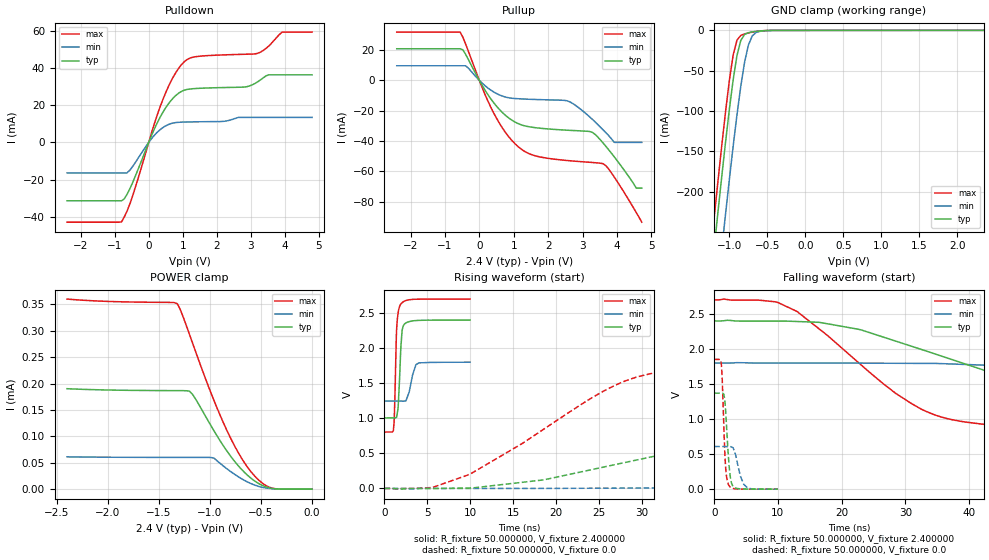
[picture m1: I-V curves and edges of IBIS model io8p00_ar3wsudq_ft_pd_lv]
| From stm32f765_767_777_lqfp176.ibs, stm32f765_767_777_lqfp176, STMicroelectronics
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|   Model io8p00_ar3wsudq_ft_pd_lv
[Model]  io8p00_ar3wsudq_ft_pd_lv
Model_type I/O
Polarity   Non-Inverting
Enable   Active-Low
Vinl =   0.720000V
Vinh =   1.680000V
Vmeas =  1.200000V
Cref =   50.000000pF
Rref =   100.000000M
Vref =   0.0V
C_comp   3.740200pF   3.683500pF   3.822900pF
[Temperature Range]   25.000000   0.125000k   -40.000000
[Pullup Reference]   2.400000V   1.800000V   2.700000V
[Pulldown Reference]   0.0V   0.0V   0.0V
[POWER Clamp Reference]   2.400000V   1.800000V   2.700000V
[GND Clamp Reference]   0.0V   0.0V   0.0V
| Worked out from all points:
|   slope of the pulldown table from 0 to 0.36 V, typ, clamps not added: 25 ohm
|   slope of the pullup table from 0 to 0.36 V, typ, clamps not added: 27.7 ohm
|   GND clamp passes 1 mA (typ) near -0.62 V on its own axis
|   rising waveform, R_fixture 50.000000, V_fixture 2.400000: 20-80 % time 329ps typ, 642ps min, 255ps max; typ from 1 V to 2.4 V
|   rising waveform, R_fixture 50.000000, V_fixture 0.0: 20-80 % time 32.3ns typ, 81.1ns min, 14.8ns max; typ from 0 V to 1.37 V
|   falling waveform, R_fixture 50.000000, V_fixture 2.400000: 20-80 % time 29.1ns typ, 72.6ns min, 15.7ns max; typ from 2.4 V to 1 V
|   falling waveform, R_fixture 50.000000, V_fixture 0.0: 20-80 % time 592ps typ, 1.02ns min, 461ps max; typ from 1.37 V to 0 V
[Pulldown]
|Voltage   I(typ)   I(min)   I(max)
-2.4V     -31.47mA   -16.45mA   -43.01mA
-800mV    -31.47mA   -16.45mA   -42.85mA
-480mV    -21.98mA   -13.17mA   -29.2mA
80mV      3.63mA     1.966mA    5.014mA
480mV     18.15mA    8.738mA    26.02mA
800mV     25.38mA    10.72mA    37.77mA
1.12V     28.53mA    11.02mA    44.6mA
2.8V      29.84mA    13.51mA    47.53mA
3.2V      32.66mA    13.51mA    48.04mA
3.52V     36.44mA    13.51mA    51.84mA
3.92V     36.44mA    13.51mA    59.49mA
4.8V      36.44mA    13.51mA    59.49mA
[Pullup]
|Voltage   I(typ)   I(min)   I(max)
-2.4V     20.89mA    9.66mA     31.89mA
-560mV    20.89mA    9.66mA     31.89mA
-400mV    17.28mA    9.66mA     24.06mA
320mV     -11.75mA   -6.207mA   -17.08mA
960mV     -26.47mA   -11.82mA   -40.02mA
1.52V     -30.88mA   -12.51mA   -49.05mA
2.56V     -32.88mA   -13.52mA   -52.9mA
3.28V     -34.25mA   -25.64mA   -54.18mA
3.6V      -41.44mA   -32.74mA   -55.03mA
3.92V     -50.46mA   -40.9mA    -63.79mA
4.56V     -71.1mA    -40.9mA    -87.26mA
4.72V     -71.1mA    -40.9mA    -93.6mA
[GND_clamp]
|Voltage   I(typ)   I(min)   I(max)
-2.4V     -1.43A     -1.515A    -1.399A
-1.25V    -315.9mA   -407.2mA   -278.2mA
-1.2V     -270.1mA   -361.3mA   -232.1mA
-1.15V    -225mA     -316mA     -186.8mA
-1.1V     -180.9mA   -271.3mA   -142.7mA
-1.05V    -138.2mA   -227.5mA   -100.5mA
-950mV    -61.14mA   -143.6mA   -30.44mA
-900mV    -31.24mA   -104.7mA   -12.15mA
-850mV    -12.5mA    -69.41mA   -6.236mA
-750mV    -2.91mA    -18.35mA   -3.195mA
-600mV    -761.5uA   -1.227mA   -751.9uA
2.35V     58.09uA    37.93uA    67.25uA
[POWER_clamp]
|Voltage   I(typ)   I(min)   I(max)
-2.4V     190.2uA    61.19uA    359.9uA
-1.32V    186.6uA    60.14uA    351.2uA
-1.29V    186.5uA    60.13uA    339.6uA
-1.2V     185.4uA    60.11uA    292.6uA
-1.17V    179.2uA    60.11uA    276.3uA
-960mV    110.2uA    58.62uA    167.5uA
-870mV    82.44uA    43.99uA    126.3uA
-750mV    50.58uA    26.92uA    78.64uA
-630mV    25.94uA    13.41uA    41.02uA
-510mV    9.22uA     4.527uA    14.97uA
-420mV    2.425uA    1.38uA     3.75uA
0V        0A         0A         0A
[Ramp]
| variable   typ   min   max
dV/dt_r  0.82230/32.32787n   0.36218/83.54610n   1.11060/14.76107n
dV/dt_f  0.83814/29.18374n   0.32664/73.67429n   1.13737/15.68093n
R_load = 50.000000
[Rising Waveform]
R_fixture= 50.000000
V_fixture= 2.400000
V_fixture_min= 1.800000
V_fixture_max= 2.700000
|time   V(typ)   V(min)   V(max)
0s        1.005V     1.245V     804.1mV
1.041ns   1.005V     1.245V     830.5mV
1.141ns   1.005V     1.245V     1.003V
1.421ns   1.018V     1.246V     2.284V
1.602ns   1.184V     1.246V     2.511V
1.882ns   1.947V     1.245V     2.624V
2.042ns   2.24V      1.245V     2.647V
2.262ns   2.332V     1.245V     2.666V
4.024ns   2.396V     1.789V     2.697V
9.97ns    2.399V     1.799V     2.699V
[Rising Waveform]
R_fixture= 50.000000
V_fixture= 0.0
V_fixture_min= 0.0
V_fixture_max= 0.0
|time   V(typ)   V(min)   V(max)
0s        6.354nV    356.5nV    2.716nV
5.506ns   -209.1uV   -118.7uV   13.13mV
9.51ns    5.648mV    -61.67uV   182.7mV
26.53ns   331.2mV    4.598mV    1.45V
31.53ns   462.1mV    7.176mV    1.651V
36.54ns   611.9mV    21.79mV    1.738V
55.56ns   1.077V     80.48mV    1.825V
77.08ns   1.305V     178.8mV    1.846V
148.1ns   1.368V     492.4mV    1.851V
249.2ns   1.369V     608.5mV    1.851V
[Falling Waveform]
R_fixture= 50.000000
V_fixture= 2.400000
V_fixture_min= 1.800000
V_fixture_max= 2.700000
|time   V(typ)   V(min)   V(max)
0s        2.399V     1.799V     2.699V
10.01ns   2.397V     1.798V     2.662V
13.01ns   2.391V     1.798V     2.533V
22.52ns   2.282V     1.798V     1.813V
31.03ns   2.036V     1.794V     1.216V
42.54ns   1.69V      1.768V     923.1mV
58.56ns   1.263V     1.716V     848.5mV
83.58ns   1.083V     1.578V     815.9mV
176.2ns   1.01V      1.275V     804.4mV
249.2ns   1.005V     1.245V     804.1mV
[Falling Waveform]
R_fixture= 50.000000
V_fixture= 0.0
V_fixture_min= 0.0
V_fixture_max= 0.0
|time   V(typ)   V(min)   V(max)
0s        1.369V     608.5mV    1.851V
1.141ns   1.369V     608.4mV    1.76V
1.722ns   1.206V     608.1mV    415.6mV
1.902ns   954.7mV    607.9mV    204.3mV
2.282ns   402.7mV    608.8mV    57.89mV
2.543ns   164mV      608.6mV    28.42mV
2.923ns   46.31mV    592.1mV    12.32mV
4.104ns   4.358mV    186.2mV    1.428mV
5.285ns   1.125mV    13.85mV    534.5uV
9.97ns    6.354nV    356.5nV    2.716nV
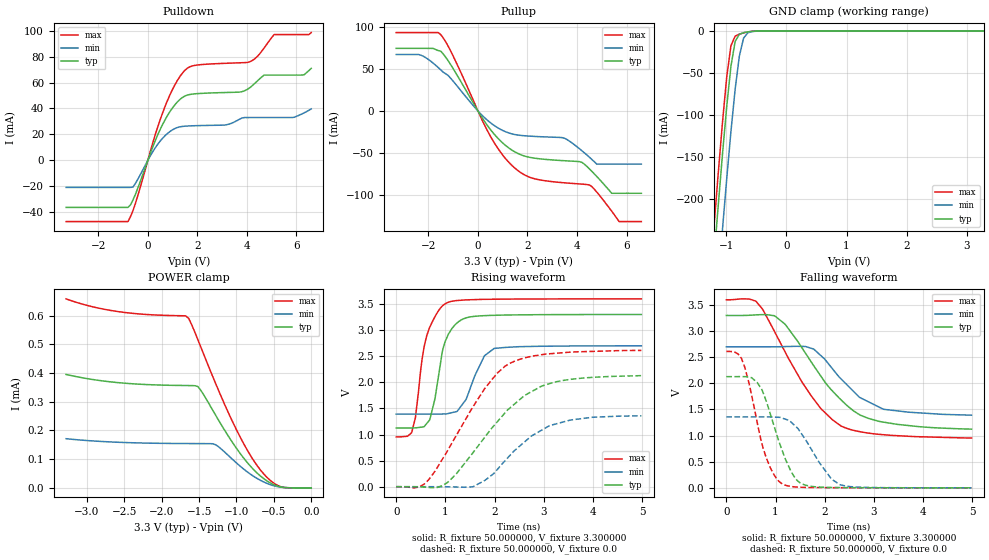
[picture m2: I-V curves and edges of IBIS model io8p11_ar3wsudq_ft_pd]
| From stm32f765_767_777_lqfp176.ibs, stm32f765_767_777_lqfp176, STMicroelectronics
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|   Model io8p11_ar3wsudq_ft_pd
[Model]  io8p11_ar3wsudq_ft_pd
Model_type I/O
Polarity   Non-Inverting
Enable   Active-Low
Vinl =   0.990000V
Vinh =   2.310000V
Vmeas =  1.650000V
Cref =   30.000000pF
Rref =   100.000000M
Vref =   0.0V
C_comp   3.843200pF   3.761700pF   3.937000pF
[Temperature Range]   25.000000   0.125000k   -40.000000
[Pullup Reference]   3.300000V   2.700000V   3.600000V
[Pulldown Reference]   0.0V   0.0V   0.0V
[POWER Clamp Reference]   3.300000V   2.700000V   3.600000V
[GND Clamp Reference]   0.0V   0.0V   0.0V
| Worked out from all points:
|   slope of the pulldown table from 0 to 0.495 V, typ, clamps not added: 20.9 ohm
|   slope of the pullup table from 0 to 0.495 V, typ, clamps not added: 22.6 ohm
|   GND clamp passes 1 mA (typ) near -0.62 V on its own axis
|   rising waveform, R_fixture 50.000000, V_fixture 3.300000: 20-80 % time 279ps typ, 352ps min, 279ps max; typ from 1.12 V to 3.3 V
|   rising waveform, R_fixture 50.000000, V_fixture 0.0: 20-80 % time 1.18ns typ, 960ps min, 1.04ns max; typ from 0 V to 2.13 V
|   falling waveform, R_fixture 50.000000, V_fixture 3.300000: 20-80 % time 1.07ns typ, 856ps min, 1.02ns max; typ from 3.3 V to 1.12 V
|   falling waveform, R_fixture 50.000000, V_fixture 0.0: 20-80 % time 466ps typ, 565ps min, 397ps max; typ from 2.13 V to 0 V
[Pulldown]
|Voltage   I(typ)   I(min)   I(max)
-3.3V     -36.18mA   -20.77mA   -47.07mA
-800mV    -36.18mA   -20.77mA   -47.07mA
-600mV    -30.5mA    -20.52mA   -38.69mA
700mV     31.4mA     19.11mA    41.71mA
1.2V      45.15mA    25.37mA    61.75mA
1.6V      50.35mA    26.5mA     71.06mA
3.1V      52.27mA    27.26mA    74.75mA
4.1V      55.7mA     33.01mA    75.8mA
4.7V      65.73mA    33.01mA    86.69mA
5.1V      65.73mA    33.01mA    96.89mA
6.3V      65.85mA    36.49mA    96.89mA
6.6V      70.9mA     39.7mA     98.44mA
[Pullup]
|Voltage   I(typ)   I(min)   I(max)
-3.3V     74.74mA    67.41mA    93.6mA
-2.3V     74.74mA    66.57mA    93.6mA
-1.5V     71.36mA    49.01mA    91.03mA
500mV     -22.07mA   -14mA      -30.03mA
1.6V      -50.64mA   -28.81mA   -70.96mA
3.5V      -59.53mA   -32.72mA   -85.92mA
4.2V      -61.52mA   -47.62mA   -87.46mA
4.5V      -69.21mA   -55.27mA   -88.44mA
4.8V      -78.37mA   -63.6mA    -97.02mA
5.4V      -98.4mA    -63.6mA    -119.7mA
5.7V      -98.4mA    -63.6mA    -132.2mA
6.6V      -98.4mA    -63.6mA    -132.2mA
[GND_clamp]
|Voltage   I(typ)   I(min)   I(max)
-3.3V     -2.324A    -2.403A    -2.297A
-1.2V     -270.2mA   -361.4mA   -232.1mA
-1.13V    -207.3mA   -298.1mA   -169mA
-1.06V    -146.7mA   -236.2mA   -108.8mA
-990mV    -90.18mA   -176.4mA   -54.97mA
-920mV    -42.21mA   -120mA     -17.69mA
-850mV    -12.58mA   -69.47mA   -6.279mA
-780mV    -3.983mA   -30.01mA   -3.9mA
-710mV    -2.112mA   -8.623mA   -2.396mA
-640mV    -1.159mA   -2.292mA   -1.234mA
-570mV    -535.1uA   -830.5uA   -490.2uA
3.28V     81.28uA    57.87uA    93.98uA
[POWER_clamp]
|Voltage   I(typ)   I(min)   I(max)
-3.28V    395.3uA    171.3uA    658.7uA
-2.6V     367.1uA    159uA      614.9uA
-1.68V    356.7uA    154.4uA    599.4uA
-1.64V    356.5uA    154.4uA    590.8uA
-1.52V    353.6uA    154.3uA    518.3uA
-1.48V    341.1uA    154.2uA    492.3uA
-1.28V    253.6uA    150.4uA    364.2uA
-960mV    123.1uA    77.56uA    181.6uA
-720mV    50.52uA    32.03uA    76.18uA
-560mV    18.94uA    12.27uA    28.65uA
-440mV    5.104uA    3.69uA     7.327uA
0V        0A         0A         0A
[Ramp]
| variable   typ   min   max
dV/dt_r  1.25826/1.16576n   0.79980/0.94582n   1.55946/1.04010n
dV/dt_f  1.27470/1.04927n   0.76302/0.82395n   1.56887/1.01446n
R_load = 50.000000
[Rising Waveform]
R_fixture= 50.000000
V_fixture= 3.300000
V_fixture_min= 2.700000
V_fixture_max= 3.600000
|time   V(typ)   V(min)   V(max)
0s        1.123V     1.391V     953.9mV
320.3ps   1.125V     1.391V     1.055V
390.4ps   1.127V     1.391V     1.324V
560.6ps   1.147V     1.391V     2.642V
680.7ps   1.281V     1.39V      3.05V
1.011ns   2.815V     1.394V     3.513V
1.421ns   3.234V     1.672V     3.578V
1.792ns   3.276V     2.504V     3.589V
1.992ns   3.283V     2.649V     3.591V
4.985ns   3.299V     2.699V     3.598V
[Rising Waveform]
R_fixture= 50.000000
V_fixture= 0.0
V_fixture_min= 0.0
V_fixture_max= 0.0
|time   V(typ)   V(min)   V(max)
0s        345.3uV    196.3uV    650.7uV
570.6ps   -7.29mV    186.7uV    49.82mV
1.061ns   94.14mV    -2.414mV   718.3mV
1.562ns   652.1mV    -573.3uV   1.531V
2.042ns   1.229V     314.7mV    2.162V
2.282ns   1.485V     568.6mV    2.348V
2.613ns   1.749V     860.6mV    2.468V
3.123ns   1.976V     1.171V     2.547V
3.994ns   2.095V     1.331V     2.592V
4.985ns   2.127V     1.357V     2.611V
[Falling Waveform]
R_fixture= 50.000000
V_fixture= 3.300000
V_fixture_min= 2.700000
V_fixture_max= 3.600000
|time   V(typ)   V(min)   V(max)
0s        3.299V     2.699V     3.598V
600.6ps   3.31V      2.699V     3.571V
740.7ps   3.314V     2.699V     3.413V
981ps     3.293V     2.7V       2.989V
1.201ns   3.124V     2.703V     2.59V
1.772ns   2.344V     2.657V     1.704V
2.342ns   1.675V     2.076V     1.178V
2.713ns   1.398V     1.73V      1.075V
3.193ns   1.258V     1.504V     1.017V
4.985ns   1.123V     1.391V     953.9mV
[Falling Waveform]
R_fixture= 50.000000
V_fixture= 0.0
V_fixture_min= 0.0
V_fixture_max= 0.0
|time   V(typ)   V(min)   V(max)
0s        2.127V     1.357V     2.611V
310.3ps   2.128V     1.357V     2.471V
470.5ps   2.115V     1.357V     1.964V
630.6ps   2.014V     1.357V     1.239V
880.9ps   1.455V     1.358V     413mV
1.131ns   727.2mV    1.337V     80.89mV
1.502ns   95.33mV    1.073V     12.51mV
2.132ns   7.615mV    175.2mV    3.177mV
2.312ns   5.456mV    59.47mV    2.808mV
4.985ns   345.3uV    196.3uV    650.7uV
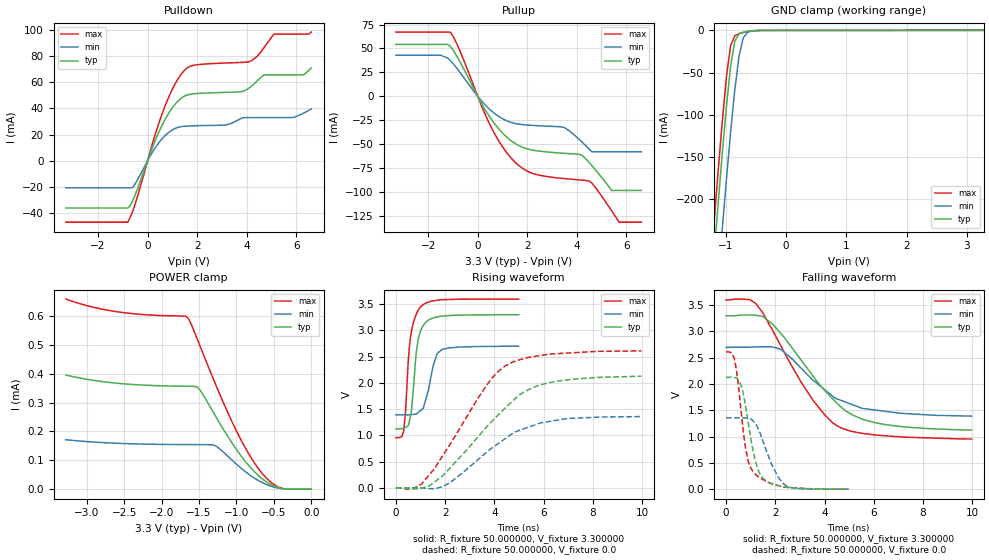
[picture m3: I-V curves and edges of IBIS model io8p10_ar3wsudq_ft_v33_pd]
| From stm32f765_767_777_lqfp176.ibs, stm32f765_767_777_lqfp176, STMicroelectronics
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|   Model io8p10_ar3wsudq_ft_v33_pd
[Model]  io8p10_ar3wsudq_ft_v33_pd
Model_type I/O
Polarity   Non-Inverting
Enable   Active-Low
Vinl =   0.990000V
Vinh =   2.310000V
Vmeas =  1.650000V
Cref =   40.000000pF
Rref =   100.000000M
Vref =   0.0V
C_comp   3.857500pF   3.760500pF   3.941700pF
[Temperature Range]   25.000000   0.125000k   -40.000000
[Pullup Reference]   3.300000V   2.700000V   3.600000V
[Pulldown Reference]   0.0V   0.0V   0.0V
[POWER Clamp Reference]   3.300000V   2.700000V   3.600000V
[GND Clamp Reference]   0.0V   0.0V   0.0V
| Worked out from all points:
|   slope of the pulldown table from 0 to 0.495 V, typ, clamps not added: 20.9 ohm
|   slope of the pullup table from 0 to 0.495 V, typ, clamps not added: 22.6 ohm
|   GND clamp passes 1 mA (typ) near -0.62 V on its own axis
|   rising waveform, R_fixture 50.000000, V_fixture 3.300000: 20-80 % time 278ps typ, 400ps min, 275ps max; typ from 1.12 V to 3.3 V
|   rising waveform, R_fixture 50.000000, V_fixture 0.0: 20-80 % time 2.56ns typ, 2.3ns min, 2.13ns max; typ from 0 V to 2.13 V
|   falling waveform, R_fixture 50.000000, V_fixture 3.300000: 20-80 % time 2.28ns typ, 2.11ns min, 2.06ns max; typ from 3.3 V to 1.12 V
|   falling waveform, R_fixture 50.000000, V_fixture 0.0: 20-80 % time 515ps typ, 708ps min, 441ps max; typ from 2.13 V to 0 V
[Pulldown]
|Voltage   I(typ)   I(min)   I(max)
-3.3V     -36.18mA   -20.77mA   -47.07mA
-800mV    -36.18mA   -20.77mA   -47.07mA
-600mV    -30.5mA    -20.52mA   -38.69mA
700mV     31.4mA     19.11mA    41.71mA
1.2V      45.15mA    25.37mA    61.75mA
1.6V      50.35mA    26.5mA     71.06mA
3.1V      52.27mA    27.26mA    74.75mA
4.1V      55.7mA     32.99mA    75.8mA
4.7V      65.71mA    32.99mA    86.63mA
5.1V      65.71mA    32.99mA    96.88mA
6.3V      65.85mA    36.49mA    96.88mA
6.6V      70.9mA     39.7mA     98.44mA
[Pullup]
|Voltage   I(typ)   I(min)   I(max)
-3.3V     54.18mA    42.91mA    67.09mA
-1.5V     54.18mA    42.91mA    67.09mA
-1.1V     51.95mA    37.28mA    66.83mA
500mV     -22.07mA   -14mA      -30.03mA
1.5V      -49.1mA    -28.3mA    -68.56mA
2.2V      -56.04mA   -30.32mA   -80.35mA
3.5V      -59.53mA   -32.72mA   -85.92mA
4.2V      -61.52mA   -47.6mA    -87.46mA
4.5V      -69.21mA   -55.15mA   -88.44mA
5.4V      -98.3mA    -57.9mA    -119.4mA
5.7V      -98.3mA    -57.9mA    -131.4mA
6.6V      -98.3mA    -57.9mA    -131.4mA
[GND_clamp]
|Voltage   I(typ)   I(min)   I(max)
-3.3V     -2.332A    -2.407A    -2.312A
-1.2V     -270.2mA   -361.4mA   -232.1mA
-1.13V    -207.3mA   -298.1mA   -169mA
-1.06V    -146.7mA   -236.2mA   -108.8mA
-990mV    -90.18mA   -176.4mA   -54.97mA
-920mV    -42.21mA   -120mA     -17.69mA
-850mV    -12.58mA   -69.47mA   -6.279mA
-780mV    -3.983mA   -30.01mA   -3.9mA
-710mV    -2.112mA   -8.623mA   -2.396mA
-640mV    -1.159mA   -2.292mA   -1.234mA
-570mV    -535.1uA   -830.5uA   -490.2uA
3.28V     81.28uA    57.87uA    93.98uA
[POWER_clamp]
|Voltage   I(typ)   I(min)   I(max)
-3.28V    395.3uA    171.3uA    658.7uA
-2.6V     367.1uA    159uA      614.9uA
-1.68V    356.7uA    154.4uA    599.4uA
-1.64V    356.5uA    154.4uA    590.8uA
-1.52V    353.6uA    154.3uA    518.3uA
-1.48V    341.1uA    154.2uA    492.3uA
-1.28V    253.6uA    150.4uA    364.2uA
-960mV    123.1uA    77.55uA    181.6uA
-720mV    50.52uA    32.03uA    76.18uA
-560mV    18.94uA    12.27uA    28.65uA
-440mV    5.104uA    3.69uA     7.327uA
0V        0A         0A         0A
[Ramp]
| variable   typ   min   max
dV/dt_r  1.26810/2.56020n   0.81246/2.31714n   1.56504/2.13233n
dV/dt_f  1.28472/2.27343n   0.77808/2.11211n   1.57535/2.06094n
R_load = 50.000000
[Rising Waveform]
R_fixture= 50.000000
V_fixture= 3.300000
V_fixture_min= 2.700000
V_fixture_max= 3.600000
|time   V(typ)   V(min)   V(max)
0s        1.123V     1.391V     953.8mV
320.3ps   1.131V     1.39V      1.098V
390.4ps   1.15V      1.39V      1.454V
510.5ps   1.199V     1.391V     2.476V
690.7ps   1.782V     1.398V     3.113V
840.8ps   2.632V     1.412V     3.325V
991ps     2.977V     1.47V      3.446V
1.682ns   3.258V     2.565V     3.576V
1.882ns   3.273V     2.639V     3.586V
4.985ns   3.299V     2.699V     3.598V
[Rising Waveform]
R_fixture= 50.000000
V_fixture= 0.0
V_fixture_min= 0.0
V_fixture_max= 0.0
|time   V(typ)   V(min)   V(max)
0s        196.3uV    83.65uV    714.9uV
560.6ps   -9.814mV   -61.21uV   -21.7mV
1.041ns   -6.992mV   -4.667mV   73.37mV
1.361ns   40.28mV    -15.48mV   251.5mV
2.182ns   370.6mV    92.42mV    818.3mV
3.804ns   1.221V     725.5mV    2.029V
4.505ns   1.555V     958.8mV    2.34V
5.165ns   1.816V     1.12V      2.46V
6.226ns   2.004V     1.263V     2.547V
9.97ns    2.127V     1.358V     2.611V
[Falling Waveform]
R_fixture= 50.000000
V_fixture= 3.300000
V_fixture_min= 2.700000
V_fixture_max= 3.600000
|time   V(typ)   V(min)   V(max)
0s        3.299V     2.699V     3.598V
961ps     3.313V     2.701V     3.604V
1.201ns   3.309V     2.706V     3.534V
1.502ns   3.282V     2.709V     3.345V
2.222ns   2.962V     2.662V     2.729V
3.524ns   2.157V     2.077V     1.697V
4.525ns   1.627V     1.715V     1.202V
5.185ns   1.4V       1.599V     1.091V
6.386ns   1.234V     1.486V     1.019V
9.97ns    1.123V     1.391V     953.8mV
[Falling Waveform]
R_fixture= 50.000000
V_fixture= 0.0
V_fixture_min= 0.0
V_fixture_max= 0.0
|time   V(typ)   V(min)   V(max)
0s        2.127V     1.358V     2.611V
340.3ps   2.124V     1.357V     2.473V
500.5ps   2.08V      1.357V     1.97V
650.7ps   1.925V     1.357V     1.314V
890.9ps   1.292V     1.346V     549.8mV
1.171ns   575.4mV    1.261V     293.2mV
1.542ns   192.7mV    852mV      171.1mV
2.132ns   64.87mV    216.9mV    66.89mV
2.422ns   39.32mV    72.24mV    35.98mV
4.985ns   196.3uV    83.65uV    714.9uV
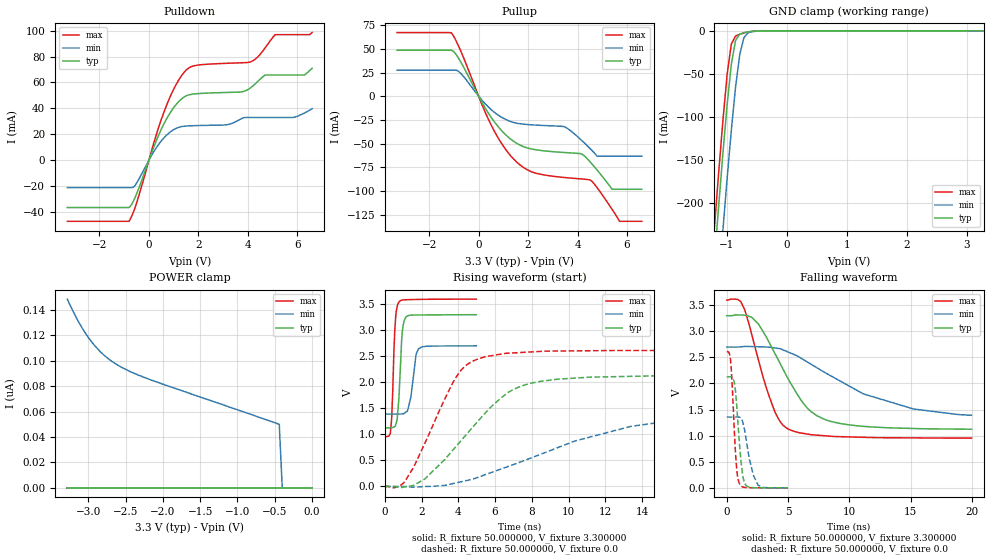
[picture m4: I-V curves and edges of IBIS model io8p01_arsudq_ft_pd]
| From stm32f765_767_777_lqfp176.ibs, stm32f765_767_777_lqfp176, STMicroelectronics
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|   Model io8p01_arsudq_ft_pd
[Model]  io8p01_arsudq_ft_pd
Model_type I/O
Polarity   Non-Inverting
Enable   Active-Low
Vinl =   0.990000V
Vinh =   2.310000V
Vmeas =  1.650000V
Cref =   50.000000pF
Rref =   100.000000M
Vref =   0.0V
C_comp   2.292100pF   2.228000pF   2.366600pF
[Temperature Range]   25.000000   0.125000k   -40.000000
[Pullup Reference]   3.300000V   2.700000V   3.600000V
[Pulldown Reference]   0.0V   0.0V   0.0V
[POWER Clamp Reference]   3.300000V   2.700000V   3.600000V
[GND Clamp Reference]   0.0V   0.0V   0.0V
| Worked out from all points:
|   slope of the pulldown table from 0 to 0.495 V, typ, clamps not added: 20.9 ohm
|   slope of the pullup table from 0 to 0.495 V, typ, clamps not added: 22.6 ohm
|   GND clamp passes 1 mA (typ) near -0.62 V on its own axis
|   rising waveform, R_fixture 50.000000, V_fixture 3.300000: 20-80 % time 192ps typ, 292ps min, 165ps max; typ from 1.12 V to 3.3 V
|   rising waveform, R_fixture 50.000000, V_fixture 0.0: 20-80 % time 3.34ns typ, 6.83ns min, 2.09ns max; typ from 0 V to 2.13 V
|   falling waveform, R_fixture 50.000000, V_fixture 3.300000: 20-80 % time 3.17ns typ, 6.84ns min, 1.99ns max; typ from 3.3 V to 1.12 V
|   falling waveform, R_fixture 50.000000, V_fixture 0.0: 20-80 % time 433ps typ, 669ps min, 341ps max; typ from 2.13 V to 0 V
[Pulldown]
|Voltage   I(typ)   I(min)   I(max)
-3.3V     -36.46mA   -21.1mA    -47.09mA
-800mV    -36.46mA   -21.1mA    -47.09mA
-600mV    -30.5mA    -20.54mA   -38.69mA
700mV     31.4mA     19.11mA    41.71mA
1.2V      45.15mA    25.37mA    61.75mA
1.6V      50.35mA    26.5mA     71.06mA
3.1V      52.27mA    27.26mA    74.75mA
4.1V      55.7mA     32.99mA    75.8mA
4.7V      65.72mA    32.99mA    86.69mA
5.1V      65.72mA    32.99mA    96.9mA
6.3V      65.87mA    36.5mA     96.9mA
6.6V      70.93mA    39.71mA    98.5mA
[Pullup]
|Voltage   I(typ)   I(min)   I(max)
-3.3V     48.54mA    27.43mA    67.18mA
-1.1V     48.54mA    27.43mA    66.9mA
-700mV    35.13mA    23.47mA    46.35mA
500mV     -22.07mA   -14mA      -30.03mA
1.5V      -49.1mA    -28.3mA    -68.56mA
2.2V      -56.04mA   -30.32mA   -80.35mA
3.5V      -59.53mA   -32.65mA   -85.92mA
4.5V      -69.06mA   -55.13mA   -88.38mA
4.8V      -78.22mA   -63.4mA    -96.84mA
5.4V      -98.3mA    -63.4mA    -119.6mA
5.7V      -98.3mA    -63.4mA    -132.1mA
6.6V      -98.3mA    -63.4mA    -132.1mA
[GND_clamp]
|Voltage   I(typ)   I(min)   I(max)
-3.3V     -2.316A    -2.396A    -2.289A
-1.2V     -265.5mA   -356.1mA   -227.2mA
-1.13V    -202.7mA   -292.9mA   -164.1mA
-1.06V    -142.2mA   -231.2mA   -104.1mA
-990mV    -85.98mA   -171.6mA   -50.73mA
-920mV    -38.81mA   -115.5mA   -15.29mA
-850mV    -11.09mA   -65.61mA   -6.016mA
-780mV    -3.793mA   -27.42mA   -3.89mA
-710mV    -2.098mA   -7.698mA   -2.396mA
-640mV    -1.159mA   -2.127mA   -1.234mA
-570mV    -535.1uA   -807.4uA   -490.2uA
3.28V     81.28uA    57.87uA    93.98uA
[POWER_clamp]
|Voltage   I(typ)   I(min)   I(max)
-3.28V    0A         148.5nA    0A
-3.2V     0A         138.6nA    0A
-3.12V    0A         129.7nA    0A
-3.04V    0A         122nA      0A
-2.96V    0A         115.3nA    0A
-2.8V     0A         105.1nA    0A
-2.6V     0A         96.44nA    0A
-2.4V     0A         90.52nA    0A
-2.16V    0A         84.97nA    0A
-440mV    0A         50.04nA    0A
-400mV    0A         0A         0A
0V        0A         0A         0A
[Ramp]
| variable   typ   min   max
dV/dt_r  1.27842/3.34427n   0.79866/6.83588n   1.56648/2.08963n
dV/dt_f  1.30206/3.17744n   0.74082/6.80385n   1.58740/1.99136n
R_load = 50.000000
[Rising Waveform]
R_fixture= 50.000000
V_fixture= 3.300000
V_fixture_min= 2.700000
V_fixture_max= 3.600000
|time   V(typ)   V(min)   V(max)
0s        1.123V     1.391V     953.9mV
300.3ps   1.125V     1.391V     1.015V
370.4ps   1.127V     1.391V     1.28V
500.5ps   1.141V     1.391V     2.636V
590.6ps   1.181V     1.391V     3.248V
760.8ps   1.665V     1.39V      3.536V
940.9ps   2.918V     1.393V     3.579V
1.161ns   3.255V     1.429V     3.586V
1.842ns   3.293V     2.643V     3.592V
4.985ns   3.299V     2.699V     3.598V
[Rising Waveform]
R_fixture= 50.000000
V_fixture= 0.0
V_fixture_min= 0.0
V_fixture_max= 0.0
|time   V(typ)   V(min)   V(max)
0s        358.4uV    205.5uV    684.6uV
1.081ns   -9.566mV   -1.992mV   89.31mV
2.162ns   138.3mV    -2.11mV    815mV
3.724ns   704.9mV    54.73mV    2.004V
4.244ns   917.6mV    95.91mV    2.267V
4.885ns   1.178V     150.8mV    2.422V
6.687ns   1.799V     380mV      2.559V
8.488ns   2.018V     618.4mV    2.593V
13.41ns   2.114V     1.154V     2.611V
19.94ns   2.127V     1.357V     2.611V
[Falling Waveform]
R_fixture= 50.000000
V_fixture= 3.300000
V_fixture_min= 2.700000
V_fixture_max= 3.600000
|time   V(typ)   V(min)   V(max)
0s        3.299V     2.699V     3.598V
880.9ps   3.314V     2.699V     3.611V
1.441ns   3.308V     2.709V     3.425V
2.563ns   3.145V     2.705V     2.469V
3.684ns   2.684V     2.689V     1.606V
4.965ns   2.107V     2.606V     1.134V
6.567ns   1.529V     2.411V     1.03V
8.248ns   1.288V     2.177V     993.4mV
15.22ns   1.138V     1.512V     957.7mV
19.94ns   1.123V     1.391V     953.9mV
[Falling Waveform]
R_fixture= 50.000000
V_fixture= 0.0
V_fixture_min= 0.0
V_fixture_max= 0.0
|time   V(typ)   V(min)   V(max)
0s        2.127V     1.357V     2.611V
300.3ps   2.129V     1.357V     2.472V
450.5ps   2.118V     1.357V     1.951V
620.6ps   2.015V     1.357V     1.081V
830.8ps   1.521V     1.359V     318mV
1.041ns   829.7mV    1.352V     78.17mV
1.451ns   99.79mV    1.116V     9.811mV
1.852ns   12.05mV    546mV      3.905mV
2.563ns   2.053mV    50.03mV    1.892mV
4.985ns   358.4uV    205.5uV    684.6uV
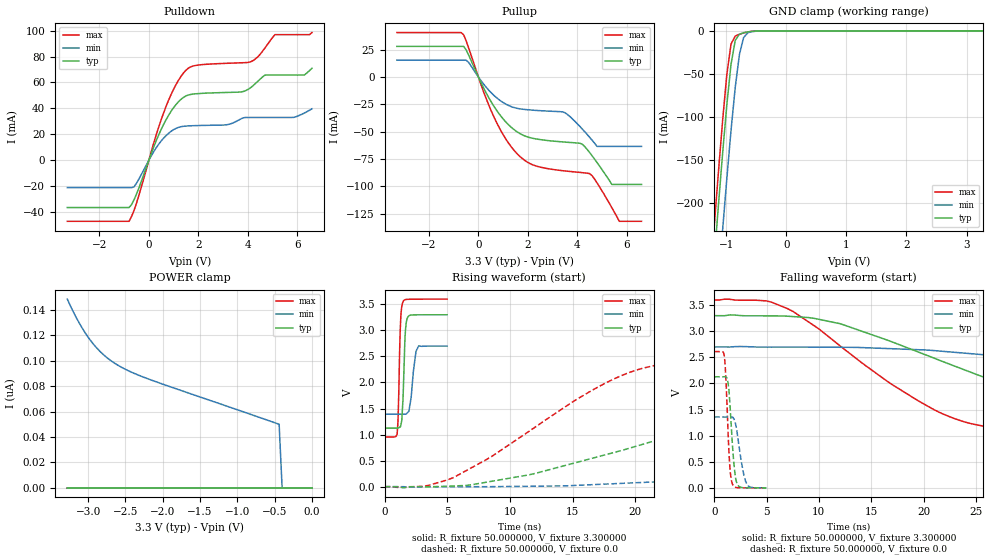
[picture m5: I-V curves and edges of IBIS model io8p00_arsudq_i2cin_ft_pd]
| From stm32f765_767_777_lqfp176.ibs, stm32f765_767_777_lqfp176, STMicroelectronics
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|   Model io8p00_arsudq_i2cin_ft_pd
[Model]  io8p00_arsudq_i2cin_ft_pd
Model_type I/O
Polarity   Non-Inverting
Enable   Active-Low
Vinl =   0.990000V
Vinh =   2.310000V
Vmeas =  1.650000V
Cref =   50.000000pF
Rref =   100.000000M
Vref =   0.0V
C_comp   2.280000pF   2.217000pF   2.355700pF
[Temperature Range]   25.000000   0.125000k   -40.000000
[Pullup Reference]   3.300000V   2.700000V   3.600000V
[Pulldown Reference]   0.0V   0.0V   0.0V
[POWER Clamp Reference]   3.300000V   2.700000V   3.600000V
[GND Clamp Reference]   0.0V   0.0V   0.0V
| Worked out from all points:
|   slope of the pulldown table from 0 to 0.495 V, typ, clamps not added: 20.9 ohm
|   slope of the pullup table from 0 to 0.495 V, typ, clamps not added: 22.6 ohm
|   GND clamp passes 1 mA (typ) near -0.62 V on its own axis
|   rising waveform, R_fixture 50.000000, V_fixture 3.300000: 20-80 % time 190ps typ, 341ps min, 164ps max; typ from 1.12 V to 3.3 V
|   rising waveform, R_fixture 50.000000, V_fixture 0.0: 20-80 % time 19.7ns typ, 51ns min, 10.4ns max; typ from 0 V to 2.13 V
|   falling waveform, R_fixture 50.000000, V_fixture 3.300000: 20-80 % time 18.4ns typ, 39.7ns min, 11.3ns max; typ from 3.3 V to 1.12 V
|   falling waveform, R_fixture 50.000000, V_fixture 0.0: 20-80 % time 433ps typ, 633ps min, 343ps max; typ from 2.13 V to 0 V
[Pulldown]
|Voltage   I(typ)   I(min)   I(max)
-3.3V     -36.46mA   -21.1mA    -47.09mA
-800mV    -36.46mA   -21.1mA    -47.09mA
-600mV    -30.5mA    -20.54mA   -38.69mA
700mV     31.4mA     19.11mA    41.71mA
1.2V      45.15mA    25.37mA    61.75mA
1.6V      50.35mA    26.5mA     71.06mA
3.1V      52.27mA    27.26mA    74.75mA
4.1V      55.7mA     32.99mA    75.8mA
4.7V      65.72mA    32.99mA    86.69mA
5.1V      65.72mA    32.99mA    96.9mA
6.3V      65.87mA    36.5mA     96.9mA
6.6V      70.93mA    39.71mA    98.5mA
[Pullup]
|Voltage   I(typ)   I(min)   I(max)
-3.3V     28.03mA    15.43mA    40.69mA
-700mV    28.03mA    15.43mA    40.69mA
-400mV    20.31mA    13.47mA    26.93mA
600mV     -25.77mA   -16.23mA   -35.13mA
1.6V      -50.64mA   -28.81mA   -70.96mA
3.5V      -59.53mA   -32.65mA   -85.92mA
4.2V      -61.43mA   -47.48mA   -87.46mA
4.5V      -69.06mA   -55.12mA   -88.38mA
4.8V      -78.22mA   -63.5mA    -96.84mA
5.4V      -98.3mA    -63.5mA    -119.6mA
5.7V      -98.3mA    -63.5mA    -132mA
6.6V      -98.3mA    -63.5mA    -132mA
[GND_clamp]
|Voltage   I(typ)   I(min)   I(max)
-3.3V     -2.318A    -2.397A    -2.291A
-1.2V     -265.5mA   -356.1mA   -227.2mA
-1.13V    -202.7mA   -292.9mA   -164.1mA
-1.06V    -142.2mA   -231.2mA   -104.1mA
-990mV    -85.98mA   -171.6mA   -50.73mA
-920mV    -38.81mA   -115.5mA   -15.29mA
-850mV    -11.09mA   -65.61mA   -6.016mA
-780mV    -3.793mA   -27.42mA   -3.89mA
-710mV    -2.098mA   -7.698mA   -2.396mA
-640mV    -1.159mA   -2.127mA   -1.234mA
-570mV    -535.1uA   -807.4uA   -490.2uA
3.28V     81.28uA    57.87uA    93.98uA
[POWER_clamp]
|Voltage   I(typ)   I(min)   I(max)
-3.28V    0A         148.5nA    0A
-3.2V     0A         138.6nA    0A
-3.12V    0A         129.7nA    0A
-3.04V    0A         122nA      0A
-2.96V    0A         115.3nA    0A
-2.8V     0A         105.1nA    0A
-2.6V     0A         96.44nA    0A
-2.4V     0A         90.52nA    0A
-2.16V    0A         84.97nA    0A
-440mV    0A         50.04nA    0A
-400mV    0A         0A         0A
0V        0A         0A         0A
[Ramp]
| variable   typ   min   max
dV/dt_r  1.27668/19.70627n   0.81486/51.02219n   1.56648/10.33869n
dV/dt_f  1.30548/18.39280n   0.78504/39.75867n   1.58747/11.31113n
R_load = 50.000000
[Rising Waveform]
R_fixture= 50.000000
V_fixture= 3.300000
V_fixture_min= 2.700000
V_fixture_max= 3.600000
|time   V(typ)   V(min)   V(max)
0s        1.123V     1.39V      953.1mV
1.001ns   1.125V     1.391V     1.025V
1.071ns   1.127V     1.391V     1.307V
1.291ns   1.183V     1.391V     3.268V
1.461ns   1.669V     1.389V     3.546V
1.632ns   2.893V     1.392V     3.588V
1.852ns   3.257V     1.427V     3.595V
2.503ns   3.297V     2.598V     3.598V
2.713ns   3.298V     2.7V       3.598V
4.985ns   3.299V     2.699V     3.599V
[Rising Waveform]
R_fixture= 50.000000
V_fixture= 0.0
V_fixture_min= 0.0
V_fixture_max= 0.0
|time   V(typ)   V(min)   V(max)
0s        11.07nV    245.8nV    19.43nV
5.506ns   13.85mV    -134.5uV   176.9mV
11.51ns   227.4mV    8.057mV    1.062V
19.52ns   738.3mV    70.21mV    2.192V
29.53ns   1.426V     200mV      2.52V
38.04ns   1.841V     350.9mV    2.579V
48.55ns   2.013V     540.4mV    2.598V
88.59ns   2.119V     1.133V     2.611V
116.6ns   2.127V     1.295V     2.611V
249.2ns   2.128V     1.358V     2.611V
[Falling Waveform]
R_fixture= 50.000000
V_fixture= 3.300000
V_fixture_min= 2.700000
V_fixture_max= 3.600000
|time   V(typ)   V(min)   V(max)
0s        3.299V     2.699V     3.599V
5.506ns   3.295V     2.697V     3.556V
12.01ns   3.146V     2.693V     2.721V
22.02ns   2.405V     2.613V     1.401V
31.53ns   1.716V     2.431V     1.069V
37.54ns   1.442V     2.286V     1.025V
46.55ns   1.274V     2.064V     992.6mV
62.56ns   1.183V     1.738V     967.8mV
90.59ns   1.141V     1.509V     955.5mV
249.2ns   1.123V     1.39V      953.1mV
[Falling Waveform]
R_fixture= 50.000000
V_fixture= 0.0
V_fixture_min= 0.0
V_fixture_max= 0.0
|time   V(typ)   V(min)   V(max)
0s        2.128V     1.358V     2.611V
981ps     2.129V     1.357V     2.504V
1.151ns   2.118V     1.357V     1.941V
1.411ns   1.864V     1.358V     680.4mV
1.542ns   1.481V     1.36V      292.9mV
1.742ns   823.7mV    1.353V     74.7mV
2.152ns   97.41mV    1.115V     5.116mV
2.823ns   2.542mV    251.9mV    218.1uV
3.123ns   773.1uV    71.02mV    111.2uV
4.985ns   11.07nV    245.8nV    19.43nV
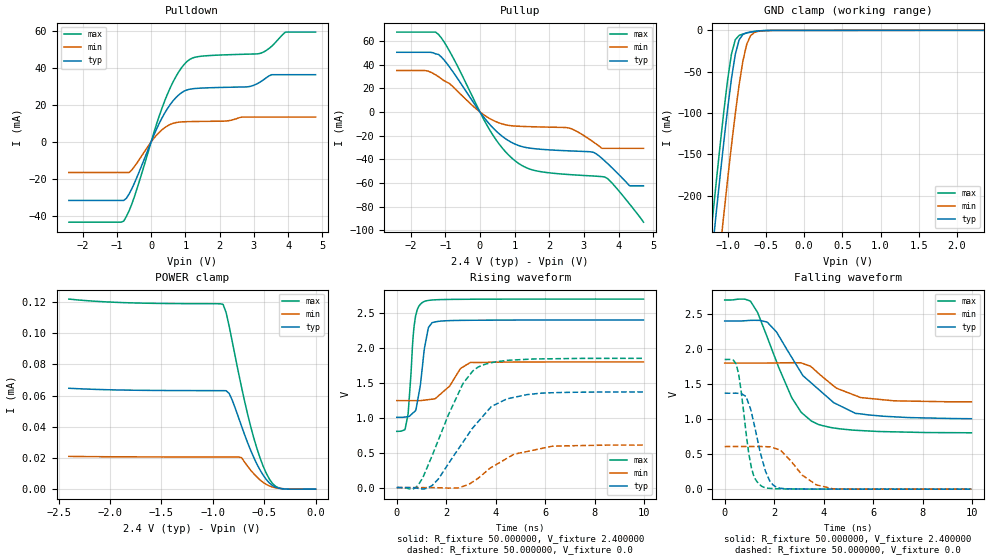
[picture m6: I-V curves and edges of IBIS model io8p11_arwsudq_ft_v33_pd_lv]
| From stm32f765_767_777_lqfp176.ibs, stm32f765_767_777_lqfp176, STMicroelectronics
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|   Model io8p11_arwsudq_ft_v33_pd_lv
[Model]  io8p11_arwsudq_ft_v33_pd_lv
Model_type I/O
Polarity   Non-Inverting
Enable   Active-Low
Vinl =   0.720000V
Vinh =   1.680000V
Vmeas =  1.200000V
Cref =   30.000000pF
Rref =   100.000000M
Vref =   0.0V
C_comp   2.828400pF   2.777000pF   2.910300pF
[Temperature Range]   25.000000   0.125000k   -40.000000
[Pullup Reference]   2.400000V   1.800000V   2.700000V
[Pulldown Reference]   0.0V   0.0V   0.0V
[POWER Clamp Reference]   2.400000V   1.800000V   2.700000V
[GND Clamp Reference]   0.0V   0.0V   0.0V
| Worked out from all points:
|   slope of the pulldown table from 0 to 0.36 V, typ, clamps not added: 25 ohm
|   slope of the pullup table from 0 to 0.36 V, typ, clamps not added: 27.7 ohm
|   GND clamp passes 1 mA (typ) near -0.62 V on its own axis
|   rising waveform, R_fixture 50.000000, V_fixture 2.400000: 20-80 % time 325ps typ, 722ps min, 219ps max; typ from 1 V to 2.4 V
|   rising waveform, R_fixture 50.000000, V_fixture 0.0: 20-80 % time 1.7ns typ, 1.62ns min, 1.34ns max; typ from 0 V to 1.37 V
|   falling waveform, R_fixture 50.000000, V_fixture 2.400000: 20-80 % time 1.95ns typ, 1.46ns min, 1.38ns max; typ from 2.4 V to 1 V
|   falling waveform, R_fixture 50.000000, V_fixture 0.0: 20-80 % time 553ps typ, 1.01ns min, 414ps max; typ from 1.37 V to 0 V
[Pulldown]
|Voltage   I(typ)   I(min)   I(max)
-2.4V     -31.66mA   -16.51mA   -43.43mA
-800mV    -31.66mA   -16.51mA   -42.86mA
-480mV    -21.98mA   -13.17mA   -29.2mA
80mV      3.63mA     1.966mA    5.014mA
480mV     18.15mA    8.738mA    26.02mA
800mV     25.38mA    10.72mA    37.77mA
1.12V     28.53mA    11.02mA    44.6mA
2.8V      29.84mA    13.48mA    47.53mA
3.2V      32.65mA    13.48mA    48.04mA
3.52V     36.42mA    13.48mA    51.83mA
3.92V     36.42mA    13.48mA    59.48mA
4.8V      36.42mA    13.48mA    59.48mA
[Pullup]
|Voltage   I(typ)   I(min)   I(max)
-2.4V     50.45mA    35.08mA    67.52mA
-1.52V    50.45mA    34.74mA    67.52mA
-1.2V     48.64mA    29.86mA    65.66mA
-800mV    34.82mA    21.93mA    47.28mA
320mV     -11.75mA   -6.207mA   -17.08mA
1.04V     -27.53mA   -11.97mA   -41.91mA
1.6V      -31.13mA   -12.58mA   -49.63mA
2.56V     -32.88mA   -13.49mA   -52.9mA
3.28V     -34.2mA    -25.51mA   -54.18mA
3.6V      -41.34mA   -30.75mA   -55mA
4.32V     -62.46mA   -30.75mA   -77.88mA
4.72V     -62.46mA   -30.75mA   -93.2mA
[GND_clamp]
|Voltage   I(typ)   I(min)   I(max)
-2.4V     -1.428A    -1.51A     -1.4A
-1.2V     -266.4mA   -356.3mA   -229.4mA
-1.15V    -221.3mA   -311mA     -184.1mA
-1.1V     -177.3mA   -266.4mA   -140mA
-1.05V    -134.8mA   -222.7mA   -97.98mA
-950mV    -58.22mA   -139.2mA   -28.55mA
-900mV    -29.04mA   -100.6mA   -11.28mA
-850mV    -11.42mA   -65.77mA   -6.081mA
-750mV    -2.864mA   -16.63mA   -3.193mA
-700mV    -1.925mA   -6.327mA   -2.195mA
-600mV    -761.3uA   -1.176mA   -751.9uA
2.35V     58.09uA    37.92uA    67.25uA
[POWER_clamp]
|Voltage   I(typ)   I(min)   I(max)
-2.4V     64.71uA    21.03uA    121.9uA
-1.86V    63.55uA    20.74uA    119.6uA
-900mV    63.18uA    20.63uA    118.5uA
-870mV    63.14uA    20.63uA    113.2uA
-840mV    61.36uA    20.62uA    104.3uA
-720mV    40.37uA    20.18uA    65.28uA
-630mV    24.69uA    12.08uA    39.85uA
-540mV    12.26uA    5.907uA    20uA
-480mV    6.236uA    3.061uA    10.23uA
-420mV    2.4uA      1.365uA    3.726uA
-360mV    667.9nA    564nA      839.6nA
0V        0A         0A         0A
[Ramp]
| variable   typ   min   max
dV/dt_r  0.82116/1.69866n   0.36919/1.69972n   1.11072/1.33701n
dV/dt_f  0.83376/1.94755n   0.33234/1.46235n   1.13584/1.38120n
R_load = 50.000000
[Rising Waveform]
R_fixture= 50.000000
V_fixture= 2.400000
V_fixture_min= 1.800000
V_fixture_max= 2.700000
|time   V(typ)   V(min)   V(max)
0s        1.005V     1.245V     804.5mV
340.3ps   1.01V      1.245V     841.3mV
460.5ps   1.015V     1.245V     1.064V
660.7ps   1.07V      1.245V     2.163V
740.7ps   1.095V     1.245V     2.411V
1.081ns   1.882V     1.25V      2.659V
1.281ns   2.293V     1.259V     2.68V
1.642ns   2.378V     1.3V       2.69V
2.983ns   2.395V     1.792V     2.696V
9.97ns    2.399V     1.799V     2.699V
[Rising Waveform]
R_fixture= 50.000000
V_fixture= 0.0
V_fixture_min= 0.0
V_fixture_max= 0.0
|time   V(typ)   V(min)   V(max)
0s        77.37uV    35.07uV    227.3uV
620.6ps   -2.463mV   18.9uV     -22.78mV
860.9ps   -11.17mV   63.78uV    32.56mV
1.441ns   33.8mV     -758.5uV   467.8mV
2.663ns   644.1mV    15.07mV    1.48V
3.283ns   941.1mV    131.6mV    1.725V
3.824ns   1.16V      289.4mV    1.788V
5.265ns   1.331V     516.5mV    1.836V
6.306ns   1.358V     593.6mV    1.844V
9.97ns    1.369V     608.5mV    1.85V
[Falling Waveform]
R_fixture= 50.000000
V_fixture= 2.400000
V_fixture_min= 1.800000
V_fixture_max= 2.700000
|time   V(typ)   V(min)   V(max)
0s        2.399V     1.799V     2.699V
1.041ns   2.408V     1.799V     2.682V
1.341ns   2.409V     1.799V     2.51V
1.722ns   2.382V     1.799V     2.165V
2.703ns   1.884V     1.804V     1.31V
3.163ns   1.619V     1.792V     1.074V
3.504ns   1.514V     1.743V     971.5mV
4.505ns   1.217V     1.443V     868mV
5.285ns   1.081V     1.335V     840.2mV
9.97ns    1.005V     1.245V     804.5mV
[Falling Waveform]
R_fixture= 50.000000
V_fixture= 0.0
V_fixture_min= 0.0
V_fixture_max= 0.0
|time   V(typ)   V(min)   V(max)
0s        1.369V     608.5mV    1.85V
460.5ps   1.369V     608.4mV    1.788V
660.7ps   1.365V     608.3mV    1.409V
860.9ps   1.322V     608.2mV    810.8mV
1.161ns   969.8mV    608.1mV    202.7mV
1.522ns   416mV      608.4mV    36.93mV
2.122ns   25.54mV    571.7mV    5.876mV
3.143ns   2.102mV    197.7mV    1.921mV
4.384ns   949.9uV    3.575mV    957.9uV
9.97ns    77.37uV    35.07uV    227.3uV
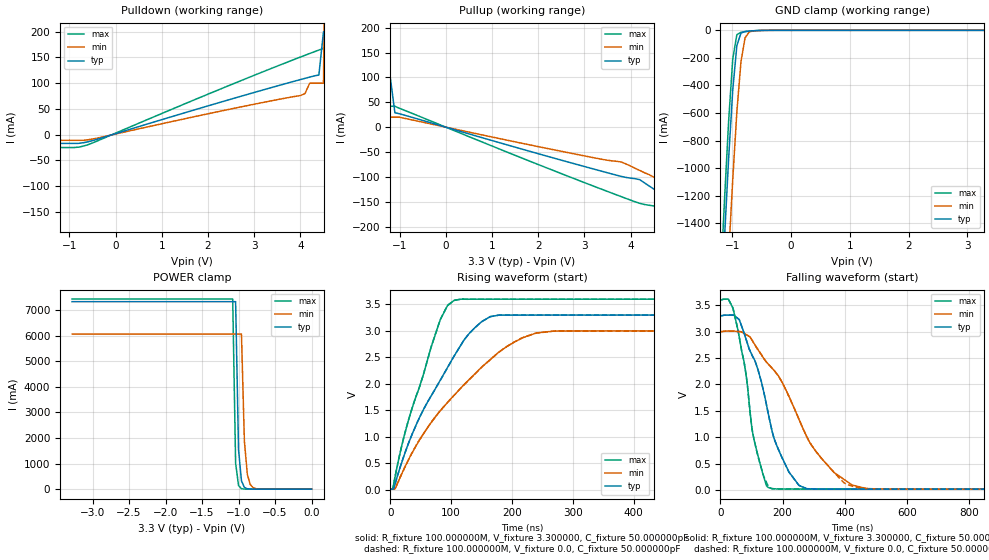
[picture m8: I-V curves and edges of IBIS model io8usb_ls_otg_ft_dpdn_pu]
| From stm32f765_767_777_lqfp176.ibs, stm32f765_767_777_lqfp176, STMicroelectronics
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|   Model io8usb_ls_otg_ft_dpdn_pu
[Model]  io8usb_ls_otg_ft_dpdn_pu
Model_type I/O
Polarity   Non-Inverting
Enable   Active-Low
Vinl =   0.990000V
Vinh =   2.310000V
Vmeas =  1.650000V
Cref =   50.000000pF
Rref =   100.000000M
Vref =   0.0V
C_comp   8.255900pF   7.991100pF   8.650600pF
[Temperature Range]   25.000000   0.125000k   -40.000000
[Pullup Reference]   3.300000V   3.000000V   3.600000V
[Pulldown Reference]   0.0V   0.0V   0.0V
[POWER Clamp Reference]   3.300000V   3.000000V   3.600000V
[GND Clamp Reference]   0.0V   0.0V   0.0V
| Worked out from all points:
|   slope of the pulldown table from 0 to 0.495 V, typ, clamps not added: 36.6 ohm
|   slope of the pullup table from 0 to 0.495 V, typ, clamps not added: 37 ohm
|   GND clamp passes 1 mA (typ) near -0.52 V on its own axis
|   POWER clamp passes 1 mA (typ) near -0.77 V on its own axis
|   rising waveform, R_fixture 100.000000M, V_fixture 3.300000, C_fixture 50.000000pF: 20-80 % time 87.8ns typ, 127ns min, 55.7ns max; typ from 0.014 V to 3.3 V
|   rising waveform, R_fixture 100.000000M, V_fixture 0.0, C_fixture 50.000000pF: 20-80 % time 87.8ns typ, 127ns min, 55.6ns max; typ from 0.014 V to 3.3 V
|   falling waveform, R_fixture 100.000000M, V_fixture 3.300000, C_fixture 50.000000pF: 20-80 % time 98.9ns typ, 172ns min, 56ns max; typ from 3.3 V to 0.014 V
|   falling waveform, R_fixture 100.000000M, V_fixture 0.0, C_fixture 50.000000pF: 20-80 % time 98.9ns typ, 172ns min, 56.1ns max; typ from 3.3 V to 0.014 V
[Pulldown]
|Voltage   I(typ)   I(min)   I(max)
-3.3V     -180mA     -10.83mA   -24.93mA
-3.2V     -16.8mA    -10.83mA   -24.93mA
-700mV    -15.57mA   -10.83mA   -22.18mA
4V        107.1mA    76mA       150.9mA
4.1V      109.5mA    80mA       154.3mA
4.2V      111.9mA    100mA      157.7mA
4.4V      116mA      100mA      164.4mA
4.5V      200mA      100mA      167.8mA
4.6V      200mA      1A         171mA
4.7V      200mA      1A         174mA
4.8V      1A         1A         200mA
6.6V      1A         1A         1A
[Pullup]
|Voltage   I(typ)   I(min)   I(max)
-3.3V     1A         1A         1A
-1.9V     1A         1A         1A
-1.8V     100mA      1A         1A
-1.7V     100mA      1A         100mA
-1.6V     100mA      1A         100mA
-1.5V     100mA      20mA       100mA
-1.3V     100mA      20mA       100mA
-1.2V     100mA      20mA       42mA
-1.1V     29mA       20mA       42mA
3.8V      -99.16mA   -70.22mA   -139.9mA
5V        -154.1mA   -123mA     -199.7mA
6.6V      -219mA     -159mA     -316mA
[GND_clamp]
|Voltage   I(typ)   I(min)   I(max)
-3.3V     -9.433A    -9.435A    -9.911A
-1.2V     -2.116A    -2.846A    -1.847A
-1.13V    -1.505A    -2.23A     -1.23A
-1.06V    -930.4mA   -1.637A    -658.9mA
-990mV    -432.7mA   -1.08A     -207.3mA
-920mV    -110.5mA   -590.3mA   -31.59mA
-850mV    -19.84mA   -226.8mA   -13.66mA
-780mV    -8.32mA    -54.05mA   -9.516mA
-710mV    -5.29mA    -11.97mA   -6.271mA
-640mV    -3.236mA   -4.296mA   -3.584mA
3.28V     0A         0A         0A
[POWER_clamp]
|Voltage   I(typ)   I(min)   I(max)
-3.28V    7.329A     6.065A     7.432A
-1.08V    7.329A     6.065A     7.432A
-1.04V    7.329A     6.065A     1.016A
-1V       1.546A     6.065A     140mA
-960mV    326.6mA    6.065A     20.26mA
-920mV    69.53mA    1.891A     3.845mA
-880mV    15.31mA    589.6mA    1.536mA
-840mV    3.837mA    184.1mA    1.157mA
-800mV    1.378mA    57.75mA    1.042mA
-720mV    664.9uA    6.031mA    894.5uA
0V        184.3nA    121.7nA    386.5nA
[Ramp]
| variable   typ   min   max
dV/dt_r  1.44862/0.11030u   1.20126/0.19832u   1.71167/65.88388n
dV/dt_f  1.45265/94.68763n   1.20371/0.16612u   1.71380/55.17967n
R_load = 100.000000
[Rising Waveform]
R_fixture= 100.000000M
V_fixture= 3.300000
V_fixture_min= 3.000000
V_fixture_max= 3.600000
C_fixture= 50.000000pF
|time   V(typ)   V(min)   V(max)
0s        14.13mV    14.39mV    16.06mV
4.004ns   13.63mV    14.38mV    22.76mV
29.36ns   862.3mV    554.7mV    1.295V
81.41ns   2.056V     1.484V     3.19V
105.4ns   2.538V     1.794V     3.581V
129.5ns   2.949V     2.082V     3.599V
164.2ns   3.271V     2.46V      3.6V
217.6ns   3.3V       2.872V     3.6V
269.6ns   3.3V       2.998V     3.6V
1.333us   3.3V       3V         3.6V
[Rising Waveform]
R_fixture= 100.000000M
V_fixture= 0.0
V_fixture_min= 0.0
V_fixture_max= 0.0
C_fixture= 50.000000pF
|time   V(typ)   V(min)   V(max)
0s        14.13mV    14.39mV    16.06mV
4.004ns   13.63mV    14.38mV    22.76mV
29.36ns   862.3mV    554.7mV    1.295V
81.41ns   2.056V     1.484V     3.195V
105.4ns   2.537V     1.794V     3.578V
129.5ns   2.949V     2.08V      3.599V
164.2ns   3.27V      2.456V     3.599V
216.2ns   3.3V       2.869V     3.6V
269.6ns   3.3V       2.999V     3.6V
1.333us   3.3V       3V         3.6V
[Falling Waveform]
R_fixture= 100.000000M
V_fixture= 3.300000
V_fixture_min= 3.000000
V_fixture_max= 3.600000
C_fixture= 50.000000pF
|time   V(typ)   V(min)   V(max)
0s        3.3V       3V         3.6V
41.37ns   3.311V     3.009V     3.418V
76.08ns   2.971V     2.964V     2.424V
105.4ns   2.509V     2.799V     1.028V
153.5ns   1.455V     2.385V     46.36mV
184.2ns   796mV      2.176V     17.84mV
252.3ns   88.57mV    1.341V     16.08mV
324.3ns   14.94mV    600.9mV    16.07mV
423.1ns   14.11mV    92.78mV    16.06mV
1.333us   14.12mV    14.36mV    16.06mV
[Falling Waveform]
R_fixture= 100.000000M
V_fixture= 0.0
V_fixture_min= 0.0
V_fixture_max= 0.0
C_fixture= 50.000000pF
|time   V(typ)   V(min)   V(max)
0s        3.3V       3V         3.6V
41.37ns   3.311V     3.009V     3.418V
76.08ns   2.971V     2.964V     2.424V
106.8ns   2.494V     2.787V     989.3mV
156.2ns   1.38V      2.368V     44.55mV
196.2ns   634.4mV    2.058V     16.76mV
252.3ns   86.81mV    1.341V     16.05mV
304.3ns   16.82mV    750mV      16.08mV
408.4ns   14.1mV     99.02mV    16.06mV
1.333us   14.12mV    14.39mV    16.07mV
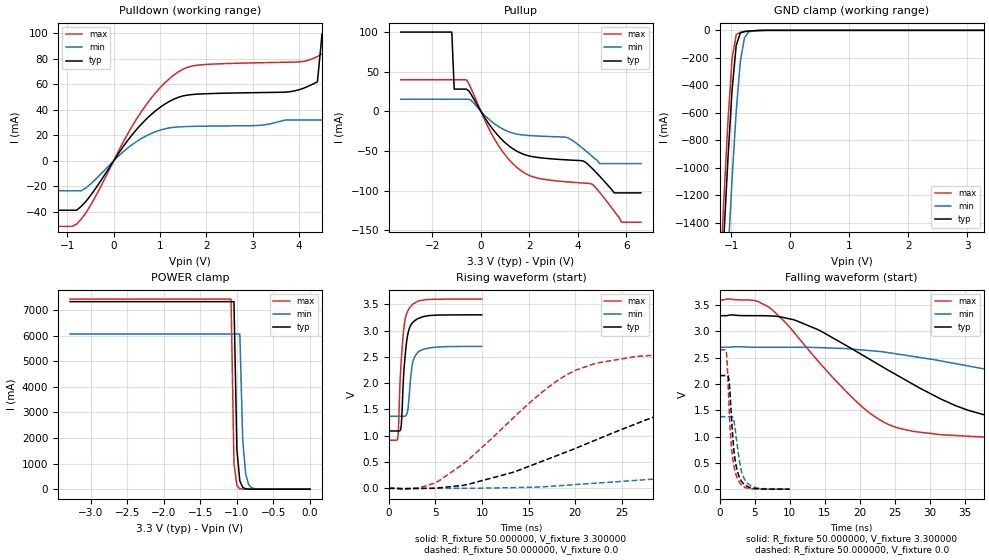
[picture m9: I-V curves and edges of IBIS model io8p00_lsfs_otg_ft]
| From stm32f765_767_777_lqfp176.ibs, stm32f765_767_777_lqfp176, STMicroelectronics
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|   Model io8p00_lsfs_otg_ft
[Model]  io8p00_lsfs_otg_ft
Model_type I/O
Polarity   Non-Inverting
Enable   Active-Low
Vinl =   0.990000V
Vinh =   2.310000V
Vmeas =  1.650000V
Cref =   50.000000pF
Rref =   100.000000M
Vref =   0.0V
C_comp   8.196500pF   7.968500pF   8.492600pF
[Temperature Range]   25.000000   0.125000k   -40.000000
[Pullup Reference]   3.300000V   2.700000V   3.600000V
[Pulldown Reference]   0.0V   0.0V   0.0V
[POWER Clamp Reference]   3.300000V   2.700000V   3.600000V
[GND Clamp Reference]   0.0V   0.0V   0.0V
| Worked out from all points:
|   slope of the pulldown table from 0 to 0.495 V, typ, clamps not added: 20.1 ohm
|   slope of the pullup table from 0 to 0.495 V, typ, clamps not added: 21.8 ohm
|   GND clamp passes 1 mA (typ) near -0.52 V on its own axis
|   POWER clamp passes 1 mA (typ) near -0.81 V on its own axis
|   rising waveform, R_fixture 50.000000, V_fixture 3.300000: 20-80 % time 527ps typ, 501ps min, 529ps max; typ from 1.09 V to 3.3 V
|   rising waveform, R_fixture 50.000000, V_fixture 0.0: 20-80 % time 19.4ns typ, 47.3ns min, 10.3ns max; typ from 0 V to 2.16 V
|   falling waveform, R_fixture 50.000000, V_fixture 3.300000: 20-80 % time 18.4ns typ, 37.6ns min, 11.3ns max; typ from 3.3 V to 1.09 V
|   falling waveform, R_fixture 50.000000, V_fixture 0.0: 20-80 % time 848ps typ, 1.01ns min, 756ps max; typ from 2.16 V to 0 V
[Pulldown]
|Voltage   I(typ)   I(min)   I(max)
-3.3V     -38.65mA   -23.43mA   -51.3mA
-800mV    -38.65mA   -23.43mA   -49.55mA
600mV     28.89mA    17.56mA    38.66mA
1.4V      49.88mA    26.66mA    69.85mA
4.1V      56.96mA    32mA       77.99mA
4.4V      62mA       32mA       81.81mA
4.5V      100mA      32mA       83.91mA
4.7V      100mA      32mA       89mA
4.8V      100mA      32mA       100mA
5.1V      100mA      32mA       100mA
5.2V      1A         1A         100mA
6.6V      1A         1A         1A
[Pullup]
|Voltage   I(typ)   I(min)   I(max)
-3.3V     100mA      15.32mA    39.89mA
-1.2V     100mA      15.32mA    39.89mA
-1.1V     27.98mA    15.32mA    39.89mA
-600mV    27.98mA    15.32mA    39.89mA
500mV     -22.94mA   -14.36mA   -31.63mA
1.3V      -46.85mA   -27.39mA   -65.63mA
2.1V      -57.1mA    -30.77mA   -82.2mA
3.5V      -61.24mA   -32.7mA    -88.93mA
4.6V      -72.4mA    -57.1mA    -92.27mA
5.5V      -103mA     -66mA      -126.2mA
5.8V      -103mA     -66mA      -140mA
6.6V      -103mA     -66mA      -140mA
[GND_clamp]
|Voltage   I(typ)   I(min)   I(max)
-3.3V     -9.479A    -9.465A    -9.974A
-1.2V     -2.125A    -2.854A    -1.857A
-1.13V    -1.511A    -2.236A    -1.236A
-1.06V    -933.3mA   -1.641A    -660.9mA
-990mV    -433.3mA   -1.082A    -206.9mA
-920mV    -110.3mA   -591mA     -31.45mA
-850mV    -19.78mA   -226.7mA   -13.65mA
-780mV    -8.311mA   -53.93mA   -9.506mA
-710mV    -5.285mA   -11.94mA   -6.262mA
-640mV    -3.232mA   -4.282mA   -3.577mA
3.28V     0A         0A         0A
[POWER_clamp]
|Voltage   I(typ)   I(min)   I(max)
-3.28V    7.328A     6.064A     7.43A
-1.08V    7.328A     6.064A     7.43A
-1.04V    7.328A     6.064A     1.015A
-1V       1.545A     6.064A     138.6mA
-960mV    325.6mA    6.064A     18.93mA
-920mV    68.64mA    1.89A      2.585mA
-880mV    14.47mA    589mA      353uA
-840mV    3.05mA     183.6mA    105.2uA
-800mV    642.9uA    57.21mA    105.2uA
-720mV    28.59uA    5.557mA    105.2uA
0V        0A         0A         0A
[Ramp]
| variable   typ   min   max
dV/dt_r  1.29641/19.41033n   0.82716/47.29580n   1.59085/10.25737n
dV/dt_f  1.32588/18.36468n   0.79746/37.71177n   1.61152/11.25114n
R_load = 50.000000
[Rising Waveform]
R_fixture= 50.000000
V_fixture= 3.300000
V_fixture_min= 2.700000
V_fixture_max= 3.600000
|time   V(typ)   V(min)   V(max)
0s        1.091V     1.371V     914mV
940.9ps   1.091V     1.371V     943.5mV
1.061ns   1.091V     1.371V     1.263V
1.281ns   1.133V     1.371V     2.294V
1.662ns   2.349V     1.371V     3.118V
1.942ns   2.836V     1.411V     3.338V
2.202ns   3.043V     1.803V     3.43V
2.503ns   3.142V     2.34V      3.489V
3.163ns   3.231V     2.595V     3.561V
9.97ns    3.3V       2.7V       3.6V
[Rising Waveform]
R_fixture= 50.000000
V_fixture= 0.0
V_fixture_min= 0.0
V_fixture_max= 0.0
|time   V(typ)   V(min)   V(max)
0s        8.709uV    4.061uV    76.57uV
5.506ns   12.08mV    -345.9uV   159.8mV
13.51ns   315.4mV    15.24mV    1.367V
20.02ns   759.8mV    71.84mV    2.244V
26.53ns   1.227V     151.8mV    2.506V
34.53ns   1.722V     278.6mV    2.599V
51.55ns   2.065V     600.7mV    2.644V
77.08ns   2.14V      1.053V     2.651V
104.1ns   2.158V     1.264V     2.651V
249.2ns   2.161V     1.379V     2.651V
[Falling Waveform]
R_fixture= 50.000000
V_fixture= 3.300000
V_fixture_min= 2.700000
V_fixture_max= 3.600000
|time   V(typ)   V(min)   V(max)
0s        3.3V       2.7V       3.6V
5.506ns   3.3V       2.7V       3.567V
11.01ns   3.201V     2.699V     2.915V
22.02ns   2.42V      2.628V     1.389V
31.53ns   1.714V     2.439V     1.036V
37.54ns   1.421V     2.291V     991.7mV
46.05ns   1.251V     2.089V     960.1mV
65.57ns   1.146V     1.678V     928.1mV
86.09ns   1.115V     1.512V     917.1mV
249.2ns   1.091V     1.371V     914mV
[Falling Waveform]
R_fixture= 50.000000
V_fixture= 0.0
V_fixture_min= 0.0
V_fixture_max= 0.0
|time   V(typ)   V(min)   V(max)
0s        2.161V     1.379V     2.651V
981ps     2.162V     1.379V     2.568V
1.321ns   2.076V     1.379V     1.617V
1.461ns   1.845V     1.38V      1.212V
1.682ns   1.367V     1.381V     797mV
2.002ns   767.3mV    1.316V     462.2mV
2.503ns   353.7mV    831.9mV    207.7mV
3.203ns   133.1mV    295.9mV    73.22mV
4.224ns   32.47mV    80.69mV    15.69mV
9.97ns    8.709uV    4.061uV    76.57uV
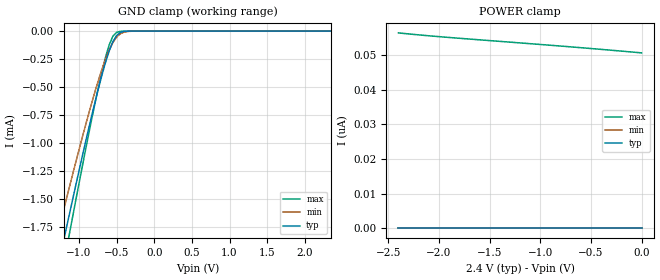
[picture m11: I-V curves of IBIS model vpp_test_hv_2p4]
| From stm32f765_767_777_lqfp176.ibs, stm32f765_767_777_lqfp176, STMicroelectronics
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|   Model vpp_test_hv_2p4
[Model]  vpp_test_hv_2p4
Model_type Input
Polarity   Non-Inverting
Vinl =   0.720000V
Vinh =   1.680000V
C_comp   1.430100pF   1.419500pF   1.431600pF
[Temperature Range]   25.000000   0.125000k   -40.000000
[Pullup Reference]   2.400000V   1.800000V   2.700000V
[Pulldown Reference]   0.0V   0.0V   0.0V
[POWER Clamp Reference]   2.400000V   1.800000V   2.700000V
[GND Clamp Reference]   0.0V   0.0V   0.0V
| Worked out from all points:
|   GND clamp passes 1 mA (typ) near -0.91 V on its own axis
[GND_clamp]
|Voltage   I(typ)   I(min)   I(max)
-2.4V     -5.694mA   -4.954mA   -6.497mA
-1.3V     -2.173mA   -1.861mA   -2.435mA
-1.25V    -2.017mA   -1.725mA   -2.255mA
-1.2V     -1.862mA   -1.59mA    -2.075mA
-1.15V    -1.708mA   -1.456mA   -1.896mA
-1.1V     -1.555mA   -1.324mA   -1.718mA
-800mV    -672.1uA   -571.7uA   -688.6uA
-650mV    -287.8uA   -256.8uA   -242.4uA
-550mV    -96.23uA   -103.6uA   -46.76uA
-500mV    -39.5uA    -54.03uA   -11.44uA
-300mV    -196.6nA   -1.209uA   0A
2.35V     0A         0A         0A
[POWER_clamp]
|Voltage   I(typ)   I(min)   I(max)
-2.4V     0A         0A         56.38nA
-2.19V    0A         0A         55.78nA
-1.98V    0A         0A         55.25nA
-750mV    0A         0A         52.46nA
-330mV    0A         0A         51.45nA
0V        0A         0A         50.6nA
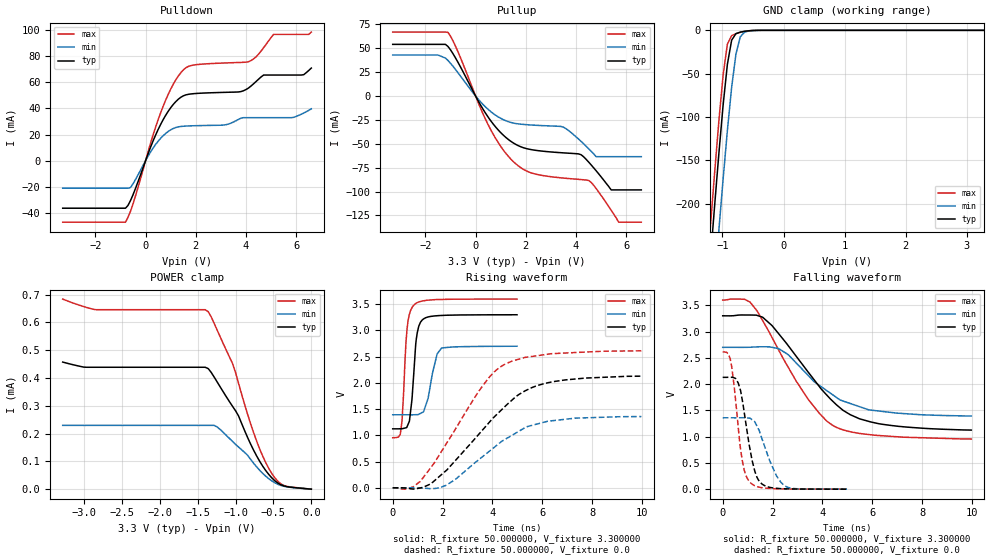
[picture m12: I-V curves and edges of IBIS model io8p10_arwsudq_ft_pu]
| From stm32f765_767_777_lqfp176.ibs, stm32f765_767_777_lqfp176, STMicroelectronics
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|   Model io8p10_arwsudq_ft_pu
[Model]  io8p10_arwsudq_ft_pu
Model_type I/O
Polarity   Non-Inverting
Enable   Active-Low
Vinl =   0.990000V
Vinh =   2.310000V
Vmeas =  1.650000V
Cref =   40.000000pF
Rref =   100.000000M
Vref =   0.0V
C_comp   2.905500pF   2.826300pF   2.987900pF
[Temperature Range]   25.000000   0.125000k   -40.000000
[Pullup Reference]   3.300000V   2.700000V   3.600000V
[Pulldown Reference]   0.0V   0.0V   0.0V
[POWER Clamp Reference]   3.300000V   2.700000V   3.600000V
[GND Clamp Reference]   0.0V   0.0V   0.0V
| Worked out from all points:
|   slope of the pulldown table from 0 to 0.495 V, typ, clamps not added: 20.9 ohm
|   slope of the pullup table from 0 to 0.495 V, typ, clamps not added: 22.6 ohm
|   GND clamp passes 1 mA (typ) near -0.62 V on its own axis
|   rising waveform, R_fixture 50.000000, V_fixture 3.300000: 20-80 % time 214ps typ, 341ps min, 188ps max; typ from 1.12 V to 3.3 V
|   rising waveform, R_fixture 50.000000, V_fixture 0.0: 20-80 % time 2.52ns typ, 2.3ns min, 2.11ns max; typ from 0.001 V to 2.13 V
|   falling waveform, R_fixture 50.000000, V_fixture 3.300000: 20-80 % time 2.27ns typ, 2.1ns min, 2.04ns max; typ from 3.3 V to 1.12 V
|   falling waveform, R_fixture 50.000000, V_fixture 0.0: 20-80 % time 461ps typ, 655ps min, 369ps max; typ from 2.13 V to 0.001 V
[Pulldown]
|Voltage   I(typ)   I(min)   I(max)
-3.3V     -36.39mA   -21.08mA   -47.09mA
-800mV    -36.39mA   -21.08mA   -47.09mA
-600mV    -30.5mA    -20.54mA   -38.69mA
700mV     31.4mA     19.11mA    41.71mA
1.2V      45.15mA    25.37mA    61.75mA
1.6V      50.35mA    26.5mA     71.06mA
3.1V      52.28mA    27.26mA    74.75mA
4.1V      55.65mA    32.92mA    75.79mA
4.7V      65.56mA    32.92mA    86.49mA
5.1V      65.56mA    32.92mA    96.69mA
6.3V      65.85mA    36.49mA    96.69mA
6.6V      70.9mA     39.7mA     98.44mA
[Pullup]
|Voltage   I(typ)   I(min)   I(max)
-3.3V     54.08mA    42.89mA    66.93mA
-1.1V     51.86mA    37.23mA    66.7mA
500mV     -22.06mA   -14mA      -30.02mA
1.5V      -49.1mA    -28.3mA    -68.56mA
2.2V      -56.04mA   -30.32mA   -80.35mA
3.5V      -59.52mA   -32.65mA   -85.91mA
4.2V      -61.44mA   -47.48mA   -87.45mA
4.5V      -69.08mA   -55.12mA   -88.39mA
4.8V      -78.23mA   -63.5mA    -96.87mA
5.4V      -98.3mA    -63.5mA    -119.6mA
5.7V      -98.3mA    -63.5mA    -132.1mA
6.6V      -98.3mA    -63.5mA    -132.1mA
[GND_clamp]
|Voltage   I(typ)   I(min)   I(max)
-3.3V     -2.319A    -2.397A    -2.292A
-1.2V     -266mA     -356.2mA   -228.4mA
-1.13V    -203.2mA   -293mA     -165.3mA
-1.06V    -142.7mA   -231.3mA   -105.2mA
-990mV    -86.51mA   -171.7mA   -51.78mA
-920mV    -39.3mA    -115.7mA   -15.93mA
-850mV    -11.37mA   -65.76mA   -6.097mA
-780mV    -3.83mA    -27.55mA   -3.88mA
-710mV    -2.09mA    -7.747mA   -2.382mA
-640mV    -1.147mA   -2.129mA   -1.22mA
-570mV    -523.9uA   -800uA     -476.9uA
3.28V     0A         0A         0A
[POWER_clamp]
|Voltage   I(typ)   I(min)   I(max)
-3.28V    457.2uA    229.4uA    683.8uA
-2.84V    438.5uA    229.4uA    645.6uA
-1.36V    433.5uA    229.4uA    638.5uA
-1.24V    384.6uA    223.2uA    570.8uA
-1.04V    298.3uA    171.8uA    452.6uA
-960mV    263.4uA    151.4uA    380.6uA
-760mV    139.5uA    92.81uA    202.3uA
-640mV    82.23uA    56.4uA     118uA
-560mV    52.51uA    37.37uA    73.96uA
-440mV    21.63uA    17.4uA     27.8uA
-360mV    11.48uA    10.27uA    13.1uA
0V        0A         0A         0A
[Ramp]
| variable   typ   min   max
dV/dt_r  1.26685/2.51870n   0.81153/2.30649n   1.56453/2.11272n
dV/dt_f  1.28208/2.25828n   0.77586/2.08361n   1.57409/2.04000n
R_load = 50.000000
[Rising Waveform]
R_fixture= 50.000000
V_fixture= 3.300000
V_fixture_min= 2.700000
V_fixture_max= 3.600000
|time   V(typ)   V(min)   V(max)
0s        1.125V     1.393V     955.6mV
310.3ps   1.127V     1.393V     1.045V
380.4ps   1.129V     1.393V     1.333V
570.6ps   1.16V      1.393V     3.002V
670.7ps   1.273V     1.393V     3.311V
830.8ps   2.085V     1.393V     3.474V
981ps     2.947V     1.396V     3.53V
1.251ns   3.225V     1.471V     3.567V
1.962ns   3.286V     2.666V     3.592V
4.985ns   3.3V       2.7V       3.599V
[Rising Waveform]
R_fixture= 50.000000
V_fixture= 0.0
V_fixture_min= 0.0
V_fixture_max= 0.0
|time   V(typ)   V(min)   V(max)
0s        1.437mV    1.241mV    1.801mV
580.6ps   -6.53mV    1.243mV    -14.6mV
1.101ns   -1.581mV   -1.499mV   121.1mV
1.522ns   75.09mV    -15.05mV   382.3mV
2.142ns   329.4mV    49.35mV    835mV
3.644ns   1.125V     610.2mV    1.968V
4.505ns   1.552V     924.3mV    2.357V
5.305ns   1.849V     1.147V     2.486V
6.206ns   2.002V     1.269V     2.547V
9.97ns    2.129V     1.359V     2.612V
[Falling Waveform]
R_fixture= 50.000000
V_fixture= 3.300000
V_fixture_min= 2.700000
V_fixture_max= 3.600000
|time   V(typ)   V(min)   V(max)
0s        3.3V       2.7V       3.599V
1.081ns   3.315V     2.702V     3.565V
1.602ns   3.273V     2.711V     3.209V
2.262ns   2.948V     2.671V     2.633V
2.643ns   2.722V     2.554V     2.308V
3.423ns   2.232V     2.167V     1.714V
4.444ns   1.66V      1.786V     1.206V
5.105ns   1.421V     1.633V     1.095V
6.246ns   1.248V     1.489V     1.023V
9.97ns    1.125V     1.393V     955.6mV
[Falling Waveform]
R_fixture= 50.000000
V_fixture= 0.0
V_fixture_min= 0.0
V_fixture_max= 0.0
|time   V(typ)   V(min)   V(max)
0s        2.129V     1.359V     2.612V
300.3ps   2.13V      1.359V     2.483V
460.5ps   2.119V     1.359V     1.952V
620.6ps   2.023V     1.359V     1.19V
860.9ps   1.468V     1.361V     369.6mV
1.091ns   770.7mV    1.351V     134.9mV
1.481ns   143.3mV    1.091V     38.04mV
2.152ns   17.81mV    258.8mV    8.338mV
2.452ns   8.995mV    77.89mV    6.196mV
4.985ns   1.437mV    1.241mV    1.801mV
